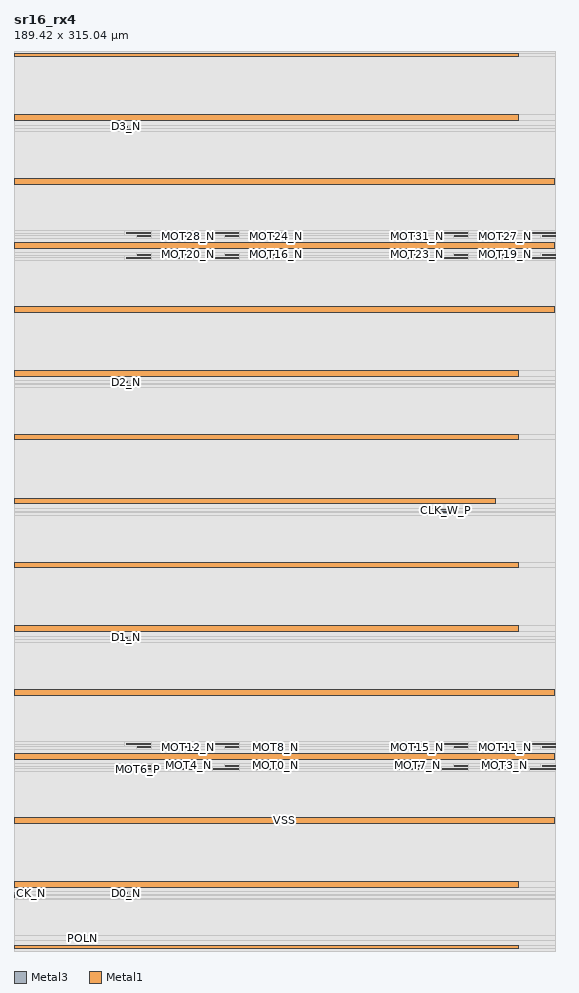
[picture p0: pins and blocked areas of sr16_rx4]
MACRO sr16_rx4
  CLASS BLOCK ;
  FOREIGN sr16_rx4 ;
  ORIGIN 0.150 1.000 ;
  SIZE 189.420 BY 315.040 ;
  PIN CK_N
    DIRECTION INPUT ;
    USE SIGNAL ;
    PORT
      LAYER Metal3 ;
        RECT 0.000 18.760 0.150 19.360 ;
    END
  END CK_N
  PIN CK_P
    DIRECTION INPUT ;
    USE SIGNAL ;
    PORT
      LAYER Metal3 ;
        RECT 0.000 17.660 0.150 18.260 ;
    END
  END CK_P
  PIN D0_N
    DIRECTION INPUT ;
    USE SIGNAL ;
    PORT
      LAYER Metal3 ;
        RECT 38.170 19.010 39.735 19.310 ;
    END
  END D0_N
  PIN D0_P
    DIRECTION INPUT ;
    USE SIGNAL ;
    PORT
      LAYER Metal3 ;
        RECT 38.170 17.910 41.980 18.210 ;
    END
  END D0_P
  PIN D1_N
    DIRECTION INPUT ;
    USE SIGNAL ;
    PORT
      LAYER Metal3 ;
        RECT 38.170 108.450 39.735 108.750 ;
    END
  END D1_N
  PIN D1_P
    DIRECTION INPUT ;
    USE SIGNAL ;
    PORT
      LAYER Metal3 ;
        RECT 38.170 107.350 41.980 107.650 ;
    END
  END D1_P
  PIN D2_N
    DIRECTION INPUT ;
    USE SIGNAL ;
    PORT
      LAYER Metal3 ;
        RECT 38.170 197.890 39.735 198.190 ;
    END
  END D2_N
  PIN D2_P
    DIRECTION INPUT ;
    USE SIGNAL ;
    PORT
      LAYER Metal3 ;
        RECT 38.170 196.790 41.980 197.090 ;
    END
  END D2_P
  PIN D3_N
    DIRECTION INPUT ;
    USE SIGNAL ;
    PORT
      LAYER Metal3 ;
        RECT 38.170 287.330 39.735 287.630 ;
    END
  END D3_N
  PIN D3_P
    DIRECTION INPUT ;
    USE SIGNAL ;
    PORT
      LAYER Metal3 ;
        RECT 38.170 286.230 41.980 286.530 ;
    END
  END D3_P
  PIN POLN
    DIRECTION INPUT ;
    USE SIGNAL ;
    PORT
      LAYER Metal3 ;
        RECT 23.370 3.010 24.040 4.030 ;
    END
  END POLN
  PIN MOT0_N
    DIRECTION OUTPUT ;
    USE SIGNAL ;
    PORT
      LAYER Metal3 ;
        RECT 89.210 63.480 93.750 64.080 ;
    END
  END MOT0_N
  PIN MOT0_P
    DIRECTION OUTPUT ;
    USE SIGNAL ;
    PORT
      LAYER Metal3 ;
        RECT 85.190 62.380 93.750 62.980 ;
    END
  END MOT0_P
  PIN MOT1_N
    DIRECTION OUTPUT ;
    USE SIGNAL ;
    PORT
      LAYER Metal3 ;
        RECT 184.730 63.480 189.270 64.080 ;
    END
  END MOT1_N
  PIN MOT1_P
    DIRECTION OUTPUT ;
    USE SIGNAL ;
    PORT
      LAYER Metal3 ;
        RECT 180.710 62.380 189.270 62.980 ;
    END
  END MOT1_P
  PIN MOT2_N
    DIRECTION OUTPUT ;
    USE SIGNAL ;
    PORT
      LAYER Metal3 ;
        RECT 73.850 63.480 78.390 64.080 ;
    END
  END MOT2_N
  PIN MOT2_P
    DIRECTION OUTPUT ;
    USE SIGNAL ;
    PORT
      LAYER Metal3 ;
        RECT 69.830 62.380 78.390 62.980 ;
    END
  END MOT2_P
  PIN MOT3_N
    DIRECTION OUTPUT ;
    USE SIGNAL ;
    PORT
      LAYER Metal3 ;
        RECT 169.370 63.480 173.910 64.080 ;
    END
  END MOT3_N
  PIN MOT3_P
    DIRECTION OUTPUT ;
    USE SIGNAL ;
    PORT
      LAYER Metal3 ;
        RECT 165.350 62.380 173.910 62.980 ;
    END
  END MOT3_P
  PIN MOT4_N
    DIRECTION OUTPUT ;
    USE SIGNAL ;
    PORT
      LAYER Metal3 ;
        RECT 58.490 63.480 63.030 64.080 ;
    END
  END MOT4_N
  PIN MOT4_P
    DIRECTION OUTPUT ;
    USE SIGNAL ;
    PORT
      LAYER Metal3 ;
        RECT 54.470 62.380 63.030 62.980 ;
    END
  END MOT4_P
  PIN MOT5_N
    DIRECTION OUTPUT ;
    USE SIGNAL ;
    PORT
      LAYER Metal3 ;
        RECT 154.010 63.480 158.550 64.080 ;
    END
  END MOT5_N
  PIN MOT5_P
    DIRECTION OUTPUT ;
    USE SIGNAL ;
    PORT
      LAYER Metal3 ;
        RECT 149.990 62.380 158.550 62.980 ;
    END
  END MOT5_P
  PIN MOT6_N
    DIRECTION OUTPUT ;
    USE SIGNAL ;
    PORT
      LAYER Metal3 ;
        RECT 43.130 63.480 47.670 64.080 ;
    END
  END MOT6_N
  PIN MOT6_P
    DIRECTION OUTPUT ;
    USE SIGNAL ;
    PORT
      LAYER Metal3 ;
        RECT 39.110 62.380 47.670 62.980 ;
    END
  END MOT6_P
  PIN MOT7_N
    DIRECTION OUTPUT ;
    USE SIGNAL ;
    PORT
      LAYER Metal3 ;
        RECT 138.650 63.480 143.190 64.080 ;
    END
  END MOT7_N
  PIN MOT7_P
    DIRECTION OUTPUT ;
    USE SIGNAL ;
    PORT
      LAYER Metal3 ;
        RECT 134.630 62.380 143.190 62.980 ;
    END
  END MOT7_P
  PIN MOT8_N
    DIRECTION OUTPUT ;
    USE SIGNAL ;
    PORT
      LAYER Metal3 ;
        RECT 89.210 70.080 93.750 70.680 ;
    END
  END MOT8_N
  PIN MOT8_P
    DIRECTION OUTPUT ;
    USE SIGNAL ;
    PORT
      LAYER Metal3 ;
        RECT 85.190 71.180 93.750 71.780 ;
    END
  END MOT8_P
  PIN MOT9_N
    DIRECTION OUTPUT ;
    USE SIGNAL ;
    PORT
      LAYER Metal3 ;
        RECT 184.730 70.080 189.270 70.680 ;
    END
  END MOT9_N
  PIN MOT9_P
    DIRECTION OUTPUT ;
    USE SIGNAL ;
    PORT
      LAYER Metal3 ;
        RECT 180.710 71.180 189.270 71.780 ;
    END
  END MOT9_P
  PIN MOT10_N
    DIRECTION OUTPUT ;
    USE SIGNAL ;
    PORT
      LAYER Metal3 ;
        RECT 73.850 70.080 78.390 70.680 ;
    END
  END MOT10_N
  PIN MOT10_P
    DIRECTION OUTPUT ;
    USE SIGNAL ;
    PORT
      LAYER Metal3 ;
        RECT 69.830 71.180 78.390 71.780 ;
    END
  END MOT10_P
  PIN MOT11_N
    DIRECTION OUTPUT ;
    USE SIGNAL ;
    PORT
      LAYER Metal3 ;
        RECT 169.370 70.080 173.910 70.680 ;
    END
  END MOT11_N
  PIN MOT11_P
    DIRECTION OUTPUT ;
    USE SIGNAL ;
    PORT
      LAYER Metal3 ;
        RECT 165.350 71.180 173.910 71.780 ;
    END
  END MOT11_P
  PIN MOT12_N
    DIRECTION OUTPUT ;
    USE SIGNAL ;
    PORT
      LAYER Metal3 ;
        RECT 58.490 70.080 63.030 70.680 ;
    END
  END MOT12_N
  PIN MOT12_P
    DIRECTION OUTPUT ;
    USE SIGNAL ;
    PORT
      LAYER Metal3 ;
        RECT 54.470 71.180 63.030 71.780 ;
    END
  END MOT12_P
  PIN MOT13_N
    DIRECTION OUTPUT ;
    USE SIGNAL ;
    PORT
      LAYER Metal3 ;
        RECT 154.010 70.080 158.550 70.680 ;
    END
  END MOT13_N
  PIN MOT13_P
    DIRECTION OUTPUT ;
    USE SIGNAL ;
    PORT
      LAYER Metal3 ;
        RECT 149.990 71.180 158.550 71.780 ;
    END
  END MOT13_P
  PIN MOT14_N
    DIRECTION OUTPUT ;
    USE SIGNAL ;
    PORT
      LAYER Metal3 ;
        RECT 43.130 70.080 47.670 70.680 ;
    END
  END MOT14_N
  PIN MOT14_P
    DIRECTION OUTPUT ;
    USE SIGNAL ;
    PORT
      LAYER Metal3 ;
        RECT 39.110 71.180 47.670 71.780 ;
    END
  END MOT14_P
  PIN MOT15_N
    DIRECTION OUTPUT ;
    USE SIGNAL ;
    PORT
      LAYER Metal3 ;
        RECT 138.650 70.080 143.190 70.680 ;
    END
  END MOT15_N
  PIN MOT15_P
    DIRECTION OUTPUT ;
    USE SIGNAL ;
    PORT
      LAYER Metal3 ;
        RECT 134.630 71.180 143.190 71.780 ;
    END
  END MOT15_P
  PIN MOT16_N
    DIRECTION OUTPUT ;
    USE SIGNAL ;
    PORT
      LAYER Metal3 ;
        RECT 89.210 242.360 93.750 242.960 ;
    END
  END MOT16_N
  PIN MOT16_P
    DIRECTION OUTPUT ;
    USE SIGNAL ;
    PORT
      LAYER Metal3 ;
        RECT 85.190 241.260 93.750 241.860 ;
    END
  END MOT16_P
  PIN MOT17_N
    DIRECTION OUTPUT ;
    USE SIGNAL ;
    PORT
      LAYER Metal3 ;
        RECT 184.730 242.360 189.270 242.960 ;
    END
  END MOT17_N
  PIN MOT17_P
    DIRECTION OUTPUT ;
    USE SIGNAL ;
    PORT
      LAYER Metal3 ;
        RECT 180.710 241.260 189.270 241.860 ;
    END
  END MOT17_P
  PIN MOT18_N
    DIRECTION OUTPUT ;
    USE SIGNAL ;
    PORT
      LAYER Metal3 ;
        RECT 73.850 242.360 78.390 242.960 ;
    END
  END MOT18_N
  PIN MOT18_P
    DIRECTION OUTPUT ;
    USE SIGNAL ;
    PORT
      LAYER Metal3 ;
        RECT 69.830 241.260 78.390 241.860 ;
    END
  END MOT18_P
  PIN MOT19_N
    DIRECTION OUTPUT ;
    USE SIGNAL ;
    PORT
      LAYER Metal3 ;
        RECT 169.370 242.360 173.910 242.960 ;
    END
  END MOT19_N
  PIN MOT19_P
    DIRECTION OUTPUT ;
    USE SIGNAL ;
    PORT
      LAYER Metal3 ;
        RECT 165.350 241.260 173.910 241.860 ;
    END
  END MOT19_P
  PIN MOT20_N
    DIRECTION OUTPUT ;
    USE SIGNAL ;
    PORT
      LAYER Metal3 ;
        RECT 58.490 242.360 63.030 242.960 ;
    END
  END MOT20_N
  PIN MOT20_P
    DIRECTION OUTPUT ;
    USE SIGNAL ;
    PORT
      LAYER Metal3 ;
        RECT 54.470 241.260 63.030 241.860 ;
    END
  END MOT20_P
  PIN MOT21_N
    DIRECTION OUTPUT ;
    USE SIGNAL ;
    PORT
      LAYER Metal3 ;
        RECT 154.010 242.360 158.550 242.960 ;
    END
  END MOT21_N
  PIN MOT21_P
    DIRECTION OUTPUT ;
    USE SIGNAL ;
    PORT
      LAYER Metal3 ;
        RECT 149.990 241.260 158.550 241.860 ;
    END
  END MOT21_P
  PIN MOT22_N
    DIRECTION OUTPUT ;
    USE SIGNAL ;
    PORT
      LAYER Metal3 ;
        RECT 43.130 242.360 47.670 242.960 ;
    END
  END MOT22_N
  PIN MOT22_P
    DIRECTION OUTPUT ;
    USE SIGNAL ;
    PORT
      LAYER Metal3 ;
        RECT 39.110 241.260 47.670 241.860 ;
    END
  END MOT22_P
  PIN MOT23_N
    DIRECTION OUTPUT ;
    USE SIGNAL ;
    PORT
      LAYER Metal3 ;
        RECT 138.650 242.360 143.190 242.960 ;
    END
  END MOT23_N
  PIN MOT23_P
    DIRECTION OUTPUT ;
    USE SIGNAL ;
    PORT
      LAYER Metal3 ;
        RECT 134.630 241.260 143.190 241.860 ;
    END
  END MOT23_P
  PIN MOT24_N
    DIRECTION OUTPUT ;
    USE SIGNAL ;
    PORT
      LAYER Metal3 ;
        RECT 89.210 248.960 93.750 249.560 ;
    END
  END MOT24_N
  PIN MOT24_P
    DIRECTION OUTPUT ;
    USE SIGNAL ;
    PORT
      LAYER Metal3 ;
        RECT 85.190 250.060 93.750 250.660 ;
    END
  END MOT24_P
  PIN MOT25_N
    DIRECTION OUTPUT ;
    USE SIGNAL ;
    PORT
      LAYER Metal3 ;
        RECT 184.730 248.960 189.270 249.560 ;
    END
  END MOT25_N
  PIN MOT25_P
    DIRECTION OUTPUT ;
    USE SIGNAL ;
    PORT
      LAYER Metal3 ;
        RECT 180.710 250.060 189.270 250.660 ;
    END
  END MOT25_P
  PIN MOT26_N
    DIRECTION OUTPUT ;
    USE SIGNAL ;
    PORT
      LAYER Metal3 ;
        RECT 73.850 248.960 78.390 249.560 ;
    END
  END MOT26_N
  PIN MOT26_P
    DIRECTION OUTPUT ;
    USE SIGNAL ;
    PORT
      LAYER Metal3 ;
        RECT 69.830 250.060 78.390 250.660 ;
    END
  END MOT26_P
  PIN MOT27_N
    DIRECTION OUTPUT ;
    USE SIGNAL ;
    PORT
      LAYER Metal3 ;
        RECT 169.370 248.960 173.910 249.560 ;
    END
  END MOT27_N
  PIN MOT27_P
    DIRECTION OUTPUT ;
    USE SIGNAL ;
    PORT
      LAYER Metal3 ;
        RECT 165.350 250.060 173.910 250.660 ;
    END
  END MOT27_P
  PIN MOT28_N
    DIRECTION OUTPUT ;
    USE SIGNAL ;
    PORT
      LAYER Metal3 ;
        RECT 58.490 248.960 63.030 249.560 ;
    END
  END MOT28_N
  PIN MOT28_P
    DIRECTION OUTPUT ;
    USE SIGNAL ;
    PORT
      LAYER Metal3 ;
        RECT 54.470 250.060 63.030 250.660 ;
    END
  END MOT28_P
  PIN MOT29_N
    DIRECTION OUTPUT ;
    USE SIGNAL ;
    PORT
      LAYER Metal3 ;
        RECT 154.010 248.960 158.550 249.560 ;
    END
  END MOT29_N
  PIN MOT29_P
    DIRECTION OUTPUT ;
    USE SIGNAL ;
    PORT
      LAYER Metal3 ;
        RECT 149.990 250.060 158.550 250.660 ;
    END
  END MOT29_P
  PIN MOT30_N
    DIRECTION OUTPUT ;
    USE SIGNAL ;
    PORT
      LAYER Metal3 ;
        RECT 43.130 248.960 47.670 249.560 ;
    END
  END MOT30_N
  PIN MOT30_P
    DIRECTION OUTPUT ;
    USE SIGNAL ;
    PORT
      LAYER Metal3 ;
        RECT 39.110 250.060 47.670 250.660 ;
    END
  END MOT30_P
  PIN MOT31_N
    DIRECTION OUTPUT ;
    USE SIGNAL ;
    PORT
      LAYER Metal3 ;
        RECT 138.650 248.960 143.190 249.560 ;
    END
  END MOT31_N
  PIN MOT31_P
    DIRECTION OUTPUT ;
    USE SIGNAL ;
    PORT
      LAYER Metal3 ;
        RECT 134.630 250.060 143.190 250.660 ;
    END
  END MOT31_P
  PIN CLK_W_N
    DIRECTION OUTPUT ;
    USE SIGNAL ;
    PORT
      LAYER Metal3 ;
        RECT 144.630 151.820 153.190 152.420 ;
    END
  END CLK_W_N
  PIN CLK_W_P
    DIRECTION OUTPUT ;
    USE SIGNAL ;
    PORT
      LAYER Metal3 ;
        RECT 148.650 152.920 153.190 153.520 ;
    END
  END CLK_W_P
  PIN VDD
    DIRECTION INOUT ;
    USE POWER ;
    PORT
      LAYER Metal1 ;
        RECT 0.000 21.360 176.560 23.360 ;
        RECT 0.000 66.080 189.120 68.080 ;
        RECT 0.000 110.800 176.560 112.800 ;
        RECT 0.000 155.520 168.400 157.520 ;
        RECT 0.000 200.240 176.560 202.240 ;
        RECT 0.000 244.960 189.120 246.960 ;
        RECT 0.000 289.680 176.560 291.680 ;
    END
  END VDD
  PIN VSS
    DIRECTION INOUT ;
    USE GROUND ;
    PORT
      LAYER Metal1 ;
        RECT 0.000 0.000 176.560 1.000 ;
        RECT 0.000 43.720 189.120 45.720 ;
        RECT 0.000 88.440 189.120 90.440 ;
        RECT 0.000 133.160 176.560 135.160 ;
        RECT 0.000 177.880 176.560 179.880 ;
        RECT 0.000 222.600 189.120 224.600 ;
        RECT 0.000 267.320 189.120 269.320 ;
        RECT 0.000 312.040 176.560 313.040 ;
    END
  END VSS
  OBS
    LAYER Metal1 ;
      RECT -0.150 -1.000 189.270 0.000 ;
      RECT -0.150 0.000 0.000 1.000 ;
      RECT 176.560 0.000 189.270 1.000 ;
      RECT -0.150 1.000 189.270 21.360 ;
      RECT -0.150 21.360 0.000 23.360 ;
      RECT 176.560 21.360 189.270 23.360 ;
      RECT -0.150 23.360 189.270 43.720 ;
      RECT -0.150 43.720 0.000 45.720 ;
      RECT 189.120 43.720 189.270 45.720 ;
      RECT -0.150 45.720 189.270 66.080 ;
      RECT -0.150 66.080 0.000 68.080 ;
      RECT 189.120 66.080 189.270 68.080 ;
      RECT -0.150 68.080 189.270 88.440 ;
      RECT -0.150 88.440 0.000 90.440 ;
      RECT 189.120 88.440 189.270 90.440 ;
      RECT -0.150 90.440 189.270 110.800 ;
      RECT -0.150 110.800 0.000 112.800 ;
      RECT 176.560 110.800 189.270 112.800 ;
      RECT -0.150 112.800 189.270 133.160 ;
      RECT -0.150 133.160 0.000 135.160 ;
      RECT 176.560 133.160 189.270 135.160 ;
      RECT -0.150 135.160 189.270 155.520 ;
      RECT -0.150 155.520 0.000 157.520 ;
      RECT 168.400 155.520 189.270 157.520 ;
      RECT -0.150 157.520 189.270 177.880 ;
      RECT -0.150 177.880 0.000 179.880 ;
      RECT 176.560 177.880 189.270 179.880 ;
      RECT -0.150 179.880 189.270 200.240 ;
      RECT -0.150 200.240 0.000 202.240 ;
      RECT 176.560 200.240 189.270 202.240 ;
      RECT -0.150 202.240 189.270 222.600 ;
      RECT -0.150 222.600 0.000 224.600 ;
      RECT 189.120 222.600 189.270 224.600 ;
      RECT -0.150 224.600 189.270 244.960 ;
      RECT -0.150 244.960 0.000 246.960 ;
      RECT 189.120 244.960 189.270 246.960 ;
      RECT -0.150 246.960 189.270 267.320 ;
      RECT -0.150 267.320 0.000 269.320 ;
      RECT 189.120 267.320 189.270 269.320 ;
      RECT -0.150 269.320 189.270 289.680 ;
      RECT -0.150 289.680 0.000 291.680 ;
      RECT 176.560 289.680 189.270 291.680 ;
      RECT -0.150 291.680 189.270 312.040 ;
      RECT -0.150 312.040 0.000 313.040 ;
      RECT 176.560 312.040 189.270 313.040 ;
      RECT -0.150 313.040 189.270 314.040 ;
    LAYER Metal2 ;
      RECT -0.150 -1.000 189.270 0.000 ;
      RECT -0.150 0.000 0.000 1.000 ;
      RECT 176.560 0.000 189.270 1.000 ;
      RECT -0.150 1.000 189.270 21.360 ;
      RECT -0.150 21.360 0.000 23.360 ;
      RECT 176.560 21.360 189.270 23.360 ;
      RECT -0.150 23.360 189.270 43.720 ;
      RECT -0.150 43.720 0.000 45.720 ;
      RECT 189.120 43.720 189.270 45.720 ;
      RECT -0.150 45.720 189.270 66.080 ;
      RECT -0.150 66.080 0.000 68.080 ;
      RECT 189.120 66.080 189.270 68.080 ;
      RECT -0.150 68.080 189.270 88.440 ;
      RECT -0.150 88.440 0.000 90.440 ;
      RECT 189.120 88.440 189.270 90.440 ;
      RECT -0.150 90.440 189.270 110.800 ;
      RECT -0.150 110.800 0.000 112.800 ;
      RECT 176.560 110.800 189.270 112.800 ;
      RECT -0.150 112.800 189.270 133.160 ;
      RECT -0.150 133.160 0.000 135.160 ;
      RECT 176.560 133.160 189.270 135.160 ;
      RECT -0.150 135.160 189.270 155.520 ;
      RECT -0.150 155.520 0.000 157.520 ;
      RECT 168.400 155.520 189.270 157.520 ;
      RECT -0.150 157.520 189.270 177.880 ;
      RECT -0.150 177.880 0.000 179.880 ;
      RECT 176.560 177.880 189.270 179.880 ;
      RECT -0.150 179.880 189.270 200.240 ;
      RECT -0.150 200.240 0.000 202.240 ;
      RECT 176.560 200.240 189.270 202.240 ;
      RECT -0.150 202.240 189.270 222.600 ;
      RECT -0.150 222.600 0.000 224.600 ;
      RECT 189.120 222.600 189.270 224.600 ;
      RECT -0.150 224.600 189.270 244.960 ;
      RECT -0.150 244.960 0.000 246.960 ;
      RECT 189.120 244.960 189.270 246.960 ;
      RECT -0.150 246.960 189.270 267.320 ;
      RECT -0.150 267.320 0.000 269.320 ;
      RECT 189.120 267.320 189.270 269.320 ;
      RECT -0.150 269.320 189.270 289.680 ;
      RECT -0.150 289.680 0.000 291.680 ;
      RECT 176.560 289.680 189.270 291.680 ;
      RECT -0.150 291.680 189.270 312.040 ;
      RECT -0.150 312.040 0.000 313.040 ;
      RECT 176.560 312.040 189.270 313.040 ;
      RECT -0.150 313.040 189.270 314.040 ;
    LAYER Metal3 ;
      RECT -0.150 -1.000 189.270 0.000 ;
      RECT -0.150 0.000 0.000 1.000 ;
      RECT 176.560 0.000 189.270 1.000 ;
      RECT -0.150 1.000 189.270 2.530 ;
      RECT -0.150 2.530 22.890 4.510 ;
      RECT 24.520 2.530 189.270 4.510 ;
      RECT -0.150 4.510 189.270 17.180 ;
      RECT 0.630 17.180 189.270 17.430 ;
      RECT 0.630 17.430 37.690 18.280 ;
      RECT 42.460 17.430 189.270 18.280 ;
      RECT 0.630 18.280 37.690 18.530 ;
      RECT 42.460 18.280 189.270 18.530 ;
      RECT 0.630 18.530 37.690 18.690 ;
      RECT 42.460 18.530 189.270 18.690 ;
      RECT 0.630 18.690 37.690 18.740 ;
      RECT 40.215 18.690 189.270 18.740 ;
      RECT 0.630 18.740 37.690 19.790 ;
      RECT 40.215 18.740 189.270 19.790 ;
      RECT 0.630 19.790 189.270 19.840 ;
      RECT -0.150 19.840 189.270 21.360 ;
      RECT -0.150 21.360 0.000 23.360 ;
      RECT 176.560 21.360 189.270 23.360 ;
      RECT -0.150 23.360 189.270 43.720 ;
      RECT -0.150 43.720 0.000 45.720 ;
      RECT 189.120 43.720 189.270 45.720 ;
      RECT -0.150 45.720 189.270 61.900 ;
      RECT -0.150 61.900 38.630 63.000 ;
      RECT 48.150 61.900 53.990 63.000 ;
      RECT 63.510 61.900 69.350 63.000 ;
      RECT 78.870 61.900 84.710 63.000 ;
      RECT 94.230 61.900 134.150 63.000 ;
      RECT 143.670 61.900 149.510 63.000 ;
      RECT 159.030 61.900 164.870 63.000 ;
      RECT 174.390 61.900 180.230 63.000 ;
      RECT -0.150 63.000 38.630 63.460 ;
      RECT 48.150 63.000 53.990 63.460 ;
      RECT 63.510 63.000 69.350 63.460 ;
      RECT 78.870 63.000 84.710 63.460 ;
      RECT 94.230 63.000 134.150 63.460 ;
      RECT 143.670 63.000 149.510 63.460 ;
      RECT 159.030 63.000 164.870 63.460 ;
      RECT 174.390 63.000 180.230 63.460 ;
      RECT -0.150 63.460 42.650 64.560 ;
      RECT 48.150 63.460 58.010 64.560 ;
      RECT 63.510 63.460 73.370 64.560 ;
      RECT 78.870 63.460 88.730 64.560 ;
      RECT 94.230 63.460 138.170 64.560 ;
      RECT 143.670 63.460 153.530 64.560 ;
      RECT 159.030 63.460 168.890 64.560 ;
      RECT 174.390 63.460 184.250 64.560 ;
      RECT -0.150 64.560 189.270 66.080 ;
      RECT -0.150 66.080 0.000 68.080 ;
      RECT 189.120 66.080 189.270 68.080 ;
      RECT -0.150 68.080 189.270 69.600 ;
      RECT -0.150 69.600 42.650 70.700 ;
      RECT 48.150 69.600 58.010 70.700 ;
      RECT 63.510 69.600 73.370 70.700 ;
      RECT 78.870 69.600 88.730 70.700 ;
      RECT 94.230 69.600 138.170 70.700 ;
      RECT 143.670 69.600 153.530 70.700 ;
      RECT 159.030 69.600 168.890 70.700 ;
      RECT 174.390 69.600 184.250 70.700 ;
      RECT -0.150 70.700 38.630 71.160 ;
      RECT 48.150 70.700 53.990 71.160 ;
      RECT 63.510 70.700 69.350 71.160 ;
      RECT 78.870 70.700 84.710 71.160 ;
      RECT 94.230 70.700 134.150 71.160 ;
      RECT 143.670 70.700 149.510 71.160 ;
      RECT 159.030 70.700 164.870 71.160 ;
      RECT 174.390 70.700 180.230 71.160 ;
      RECT -0.150 71.160 38.630 72.260 ;
      RECT 48.150 71.160 53.990 72.260 ;
      RECT 63.510 71.160 69.350 72.260 ;
      RECT 78.870 71.160 84.710 72.260 ;
      RECT 94.230 71.160 134.150 72.260 ;
      RECT 143.670 71.160 149.510 72.260 ;
      RECT 159.030 71.160 164.870 72.260 ;
      RECT 174.390 71.160 180.230 72.260 ;
      RECT -0.150 72.260 189.270 88.440 ;
      RECT -0.150 88.440 0.000 90.440 ;
      RECT 189.120 88.440 189.270 90.440 ;
      RECT -0.150 90.440 189.270 106.870 ;
      RECT -0.150 106.870 37.690 107.970 ;
      RECT 42.460 106.870 189.270 107.970 ;
      RECT -0.150 107.970 37.690 108.130 ;
      RECT 42.460 107.970 189.270 108.130 ;
      RECT -0.150 108.130 37.690 109.230 ;
      RECT 40.215 108.130 189.270 109.230 ;
      RECT -0.150 109.230 189.270 110.800 ;
      RECT -0.150 110.800 0.000 112.800 ;
      RECT 176.560 110.800 189.270 112.800 ;
      RECT -0.150 112.800 189.270 133.160 ;
      RECT -0.150 133.160 0.000 135.160 ;
      RECT 176.560 133.160 189.270 135.160 ;
      RECT -0.150 135.160 189.270 151.340 ;
      RECT -0.150 151.340 144.150 152.440 ;
      RECT 153.670 151.340 189.270 152.440 ;
      RECT -0.150 152.440 144.150 152.900 ;
      RECT 153.670 152.440 189.270 152.900 ;
      RECT -0.150 152.900 148.170 154.000 ;
      RECT 153.670 152.900 189.270 154.000 ;
      RECT -0.150 154.000 189.270 155.520 ;
      RECT -0.150 155.520 0.000 157.520 ;
      RECT 168.400 155.520 189.270 157.520 ;
      RECT -0.150 157.520 189.270 177.880 ;
      RECT -0.150 177.880 0.000 179.880 ;
      RECT 176.560 177.880 189.270 179.880 ;
      RECT -0.150 179.880 189.270 196.310 ;
      RECT -0.150 196.310 37.690 197.410 ;
      RECT 42.460 196.310 189.270 197.410 ;
      RECT -0.150 197.410 37.690 197.570 ;
      RECT 42.460 197.410 189.270 197.570 ;
      RECT -0.150 197.570 37.690 198.670 ;
      RECT 40.215 197.570 189.270 198.670 ;
      RECT -0.150 198.670 189.270 200.240 ;
      RECT -0.150 200.240 0.000 202.240 ;
      RECT 176.560 200.240 189.270 202.240 ;
      RECT -0.150 202.240 189.270 222.600 ;
      RECT -0.150 222.600 0.000 224.600 ;
      RECT 189.120 222.600 189.270 224.600 ;
      RECT -0.150 224.600 189.270 240.780 ;
      RECT -0.150 240.780 38.630 241.880 ;
      RECT 48.150 240.780 53.990 241.880 ;
      RECT 63.510 240.780 69.350 241.880 ;
      RECT 78.870 240.780 84.710 241.880 ;
      RECT 94.230 240.780 134.150 241.880 ;
      RECT 143.670 240.780 149.510 241.880 ;
      RECT 159.030 240.780 164.870 241.880 ;
      RECT 174.390 240.780 180.230 241.880 ;
      RECT -0.150 241.880 38.630 242.340 ;
      RECT 48.150 241.880 53.990 242.340 ;
      RECT 63.510 241.880 69.350 242.340 ;
      RECT 78.870 241.880 84.710 242.340 ;
      RECT 94.230 241.880 134.150 242.340 ;
      RECT 143.670 241.880 149.510 242.340 ;
      RECT 159.030 241.880 164.870 242.340 ;
      RECT 174.390 241.880 180.230 242.340 ;
      RECT -0.150 242.340 42.650 243.440 ;
      RECT 48.150 242.340 58.010 243.440 ;
      RECT 63.510 242.340 73.370 243.440 ;
      RECT 78.870 242.340 88.730 243.440 ;
      RECT 94.230 242.340 138.170 243.440 ;
      RECT 143.670 242.340 153.530 243.440 ;
      RECT 159.030 242.340 168.890 243.440 ;
      RECT 174.390 242.340 184.250 243.440 ;
      RECT -0.150 243.440 189.270 244.960 ;
      RECT -0.150 244.960 0.000 246.960 ;
      RECT 189.120 244.960 189.270 246.960 ;
      RECT -0.150 246.960 189.270 248.480 ;
      RECT -0.150 248.480 42.650 249.580 ;
      RECT 48.150 248.480 58.010 249.580 ;
      RECT 63.510 248.480 73.370 249.580 ;
      RECT 78.870 248.480 88.730 249.580 ;
      RECT 94.230 248.480 138.170 249.580 ;
      RECT 143.670 248.480 153.530 249.580 ;
      RECT 159.030 248.480 168.890 249.580 ;
      RECT 174.390 248.480 184.250 249.580 ;
      RECT -0.150 249.580 38.630 250.040 ;
      RECT 48.150 249.580 53.990 250.040 ;
      RECT 63.510 249.580 69.350 250.040 ;
      RECT 78.870 249.580 84.710 250.040 ;
      RECT 94.230 249.580 134.150 250.040 ;
      RECT 143.670 249.580 149.510 250.040 ;
      RECT 159.030 249.580 164.870 250.040 ;
      RECT 174.390 249.580 180.230 250.040 ;
      RECT -0.150 250.040 38.630 251.140 ;
      RECT 48.150 250.040 53.990 251.140 ;
      RECT 63.510 250.040 69.350 251.140 ;
      RECT 78.870 250.040 84.710 251.140 ;
      RECT 94.230 250.040 134.150 251.140 ;
      RECT 143.670 250.040 149.510 251.140 ;
      RECT 159.030 250.040 164.870 251.140 ;
      RECT 174.390 250.040 180.230 251.140 ;
      RECT -0.150 251.140 189.270 267.320 ;
      RECT -0.150 267.320 0.000 269.320 ;
      RECT 189.120 267.320 189.270 269.320 ;
      RECT -0.150 269.320 189.270 285.750 ;
      RECT -0.150 285.750 37.690 286.850 ;
      RECT 42.460 285.750 189.270 286.850 ;
      RECT -0.150 286.850 37.690 287.010 ;
      RECT 42.460 286.850 189.270 287.010 ;
      RECT -0.150 287.010 37.690 288.110 ;
      RECT 40.215 287.010 189.270 288.110 ;
      RECT -0.150 288.110 189.270 289.680 ;
      RECT -0.150 289.680 0.000 291.680 ;
      RECT 176.560 289.680 189.270 291.680 ;
      RECT -0.150 291.680 189.270 312.040 ;
      RECT -0.150 312.040 0.000 313.040 ;
      RECT 176.560 312.040 189.270 313.040 ;
      RECT -0.150 313.040 189.270 314.040 ;
    LAYER Metal4 ;
      RECT -0.150 -1.000 189.270 0.000 ;
      RECT -0.150 0.000 0.000 1.000 ;
      RECT 176.560 0.000 189.270 1.000 ;
      RECT -0.150 1.000 189.270 2.530 ;
      RECT -0.150 2.530 22.890 4.510 ;
      RECT 24.520 2.530 189.270 4.510 ;
      RECT -0.150 4.510 189.270 17.180 ;
      RECT 0.630 17.180 189.270 17.430 ;
      RECT 0.630 17.430 37.690 18.280 ;
      RECT 42.460 17.430 189.270 18.280 ;
      RECT 0.630 18.280 37.690 18.530 ;
      RECT 42.460 18.280 189.270 18.530 ;
      RECT 0.630 18.530 37.690 18.690 ;
      RECT 42.460 18.530 189.270 18.690 ;
      RECT 0.630 18.690 37.690 18.740 ;
      RECT 40.215 18.690 189.270 18.740 ;
      RECT 0.630 18.740 37.690 19.790 ;
      RECT 40.215 18.740 189.270 19.790 ;
      RECT 0.630 19.790 189.270 19.840 ;
      RECT -0.150 19.840 189.270 21.360 ;
      RECT -0.150 21.360 0.000 23.360 ;
      RECT 176.560 21.360 189.270 23.360 ;
      RECT -0.150 23.360 189.270 43.720 ;
      RECT -0.150 43.720 0.000 45.720 ;
      RECT 189.120 43.720 189.270 45.720 ;
      RECT -0.150 45.720 189.270 61.900 ;
      RECT -0.150 61.900 38.630 63.000 ;
      RECT 48.150 61.900 53.990 63.000 ;
      RECT 63.510 61.900 69.350 63.000 ;
      RECT 78.870 61.900 84.710 63.000 ;
      RECT 94.230 61.900 134.150 63.000 ;
      RECT 143.670 61.900 149.510 63.000 ;
      RECT 159.030 61.900 164.870 63.000 ;
      RECT 174.390 61.900 180.230 63.000 ;
      RECT -0.150 63.000 38.630 63.460 ;
      RECT 48.150 63.000 53.990 63.460 ;
      RECT 63.510 63.000 69.350 63.460 ;
      RECT 78.870 63.000 84.710 63.460 ;
      RECT 94.230 63.000 134.150 63.460 ;
      RECT 143.670 63.000 149.510 63.460 ;
      RECT 159.030 63.000 164.870 63.460 ;
      RECT 174.390 63.000 180.230 63.460 ;
      RECT -0.150 63.460 42.650 64.560 ;
      RECT 48.150 63.460 58.010 64.560 ;
      RECT 63.510 63.460 73.370 64.560 ;
      RECT 78.870 63.460 88.730 64.560 ;
      RECT 94.230 63.460 138.170 64.560 ;
      RECT 143.670 63.460 153.530 64.560 ;
      RECT 159.030 63.460 168.890 64.560 ;
      RECT 174.390 63.460 184.250 64.560 ;
      RECT -0.150 64.560 189.270 66.080 ;
      RECT -0.150 66.080 0.000 68.080 ;
      RECT 189.120 66.080 189.270 68.080 ;
      RECT -0.150 68.080 189.270 69.600 ;
      RECT -0.150 69.600 42.650 70.700 ;
      RECT 48.150 69.600 58.010 70.700 ;
      RECT 63.510 69.600 73.370 70.700 ;
      RECT 78.870 69.600 88.730 70.700 ;
      RECT 94.230 69.600 138.170 70.700 ;
      RECT 143.670 69.600 153.530 70.700 ;
      RECT 159.030 69.600 168.890 70.700 ;
      RECT 174.390 69.600 184.250 70.700 ;
      RECT -0.150 70.700 38.630 71.160 ;
      RECT 48.150 70.700 53.990 71.160 ;
      RECT 63.510 70.700 69.350 71.160 ;
      RECT 78.870 70.700 84.710 71.160 ;
      RECT 94.230 70.700 134.150 71.160 ;
      RECT 143.670 70.700 149.510 71.160 ;
      RECT 159.030 70.700 164.870 71.160 ;
      RECT 174.390 70.700 180.230 71.160 ;
      RECT -0.150 71.160 38.630 72.260 ;
      RECT 48.150 71.160 53.990 72.260 ;
      RECT 63.510 71.160 69.350 72.260 ;
      RECT 78.870 71.160 84.710 72.260 ;
      RECT 94.230 71.160 134.150 72.260 ;
      RECT 143.670 71.160 149.510 72.260 ;
      RECT 159.030 71.160 164.870 72.260 ;
      RECT 174.390 71.160 180.230 72.260 ;
      RECT -0.150 72.260 189.270 88.440 ;
      RECT -0.150 88.440 0.000 90.440 ;
      RECT 189.120 88.440 189.270 90.440 ;
      RECT -0.150 90.440 189.270 106.870 ;
      RECT -0.150 106.870 37.690 107.970 ;
      RECT 42.460 106.870 189.270 107.970 ;
      RECT -0.150 107.970 37.690 108.130 ;
      RECT 42.460 107.970 189.270 108.130 ;
      RECT -0.150 108.130 37.690 109.230 ;
      RECT 40.215 108.130 189.270 109.230 ;
      RECT -0.150 109.230 189.270 110.800 ;
      RECT -0.150 110.800 0.000 112.800 ;
      RECT 176.560 110.800 189.270 112.800 ;
      RECT -0.150 112.800 189.270 133.160 ;
      RECT -0.150 133.160 0.000 135.160 ;
      RECT 176.560 133.160 189.270 135.160 ;
      RECT -0.150 135.160 189.270 151.340 ;
      RECT -0.150 151.340 144.150 152.440 ;
      RECT 153.670 151.340 189.270 152.440 ;
      RECT -0.150 152.440 144.150 152.900 ;
      RECT 153.670 152.440 189.270 152.900 ;
      RECT -0.150 152.900 148.170 154.000 ;
      RECT 153.670 152.900 189.270 154.000 ;
      RECT -0.150 154.000 189.270 155.520 ;
      RECT -0.150 155.520 0.000 157.520 ;
      RECT 168.400 155.520 189.270 157.520 ;
      RECT -0.150 157.520 189.270 177.880 ;
      RECT -0.150 177.880 0.000 179.880 ;
      RECT 176.560 177.880 189.270 179.880 ;
      RECT -0.150 179.880 189.270 196.310 ;
      RECT -0.150 196.310 37.690 197.410 ;
      RECT 42.460 196.310 189.270 197.410 ;
      RECT -0.150 197.410 37.690 197.570 ;
      RECT 42.460 197.410 189.270 197.570 ;
      RECT -0.150 197.570 37.690 198.670 ;
      RECT 40.215 197.570 189.270 198.670 ;
      RECT -0.150 198.670 189.270 200.240 ;
      RECT -0.150 200.240 0.000 202.240 ;
      RECT 176.560 200.240 189.270 202.240 ;
      RECT -0.150 202.240 189.270 222.600 ;
      RECT -0.150 222.600 0.000 224.600 ;
      RECT 189.120 222.600 189.270 224.600 ;
      RECT -0.150 224.600 189.270 240.780 ;
      RECT -0.150 240.780 38.630 241.880 ;
      RECT 48.150 240.780 53.990 241.880 ;
      RECT 63.510 240.780 69.350 241.880 ;
      RECT 78.870 240.780 84.710 241.880 ;
      RECT 94.230 240.780 134.150 241.880 ;
      RECT 143.670 240.780 149.510 241.880 ;
      RECT 159.030 240.780 164.870 241.880 ;
      RECT 174.390 240.780 180.230 241.880 ;
      RECT -0.150 241.880 38.630 242.340 ;
      RECT 48.150 241.880 53.990 242.340 ;
      RECT 63.510 241.880 69.350 242.340 ;
      RECT 78.870 241.880 84.710 242.340 ;
      RECT 94.230 241.880 134.150 242.340 ;
      RECT 143.670 241.880 149.510 242.340 ;
      RECT 159.030 241.880 164.870 242.340 ;
      RECT 174.390 241.880 180.230 242.340 ;
      RECT -0.150 242.340 42.650 243.440 ;
      RECT 48.150 242.340 58.010 243.440 ;
      RECT 63.510 242.340 73.370 243.440 ;
      RECT 78.870 242.340 88.730 243.440 ;
      RECT 94.230 242.340 138.170 243.440 ;
      RECT 143.670 242.340 153.530 243.440 ;
      RECT 159.030 242.340 168.890 243.440 ;
      RECT 174.390 242.340 184.250 243.440 ;
      RECT -0.150 243.440 189.270 244.960 ;
      RECT -0.150 244.960 0.000 246.960 ;
      RECT 189.120 244.960 189.270 246.960 ;
      RECT -0.150 246.960 189.270 248.480 ;
      RECT -0.150 248.480 42.650 249.580 ;
      RECT 48.150 248.480 58.010 249.580 ;
      RECT 63.510 248.480 73.370 249.580 ;
      RECT 78.870 248.480 88.730 249.580 ;
      RECT 94.230 248.480 138.170 249.580 ;
      RECT 143.670 248.480 153.530 249.580 ;
      RECT 159.030 248.480 168.890 249.580 ;
      RECT 174.390 248.480 184.250 249.580 ;
      RECT -0.150 249.580 38.630 250.040 ;
      RECT 48.150 249.580 53.990 250.040 ;
      RECT 63.510 249.580 69.350 250.040 ;
      RECT 78.870 249.580 84.710 250.040 ;
      RECT 94.230 249.580 134.150 250.040 ;
      RECT 143.670 249.580 149.510 250.040 ;
      RECT 159.030 249.580 164.870 250.040 ;
      RECT 174.390 249.580 180.230 250.040 ;
      RECT -0.150 250.040 38.630 251.140 ;
      RECT 48.150 250.040 53.990 251.140 ;
      RECT 63.510 250.040 69.350 251.140 ;
      RECT 78.870 250.040 84.710 251.140 ;
      RECT 94.230 250.040 134.150 251.140 ;
      RECT 143.670 250.040 149.510 251.140 ;
      RECT 159.030 250.040 164.870 251.140 ;
      RECT 174.390 250.040 180.230 251.140 ;
      RECT -0.150 251.140 189.270 267.320 ;
      RECT -0.150 267.320 0.000 269.320 ;
      RECT 189.120 267.320 189.270 269.320 ;
      RECT -0.150 269.320 189.270 285.750 ;
      RECT -0.150 285.750 37.690 286.850 ;
      RECT 42.460 285.750 189.270 286.850 ;
      RECT -0.150 286.850 37.690 287.010 ;
      RECT 42.460 286.850 189.270 287.010 ;
      RECT -0.150 287.010 37.690 288.110 ;
      RECT 40.215 287.010 189.270 288.110 ;
      RECT -0.150 288.110 189.270 289.680 ;
      RECT -0.150 289.680 0.000 291.680 ;
      RECT 176.560 289.680 189.270 291.680 ;
      RECT -0.150 291.680 189.270 312.040 ;
      RECT -0.150 312.040 0.000 313.040 ;
      RECT 176.560 312.040 189.270 313.040 ;
      RECT -0.150 313.040 189.270 314.040 ;
  END
END sr16_rx4
